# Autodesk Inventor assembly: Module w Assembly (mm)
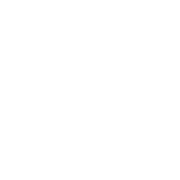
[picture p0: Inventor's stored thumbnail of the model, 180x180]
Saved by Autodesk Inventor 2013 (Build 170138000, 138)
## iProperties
Created: 2006-10
Part Number: Module w Assembly (mm)
Document SubType Name: Assembly
Designer: Wally Jones
Author: Wally Jones
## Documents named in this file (1)
- E:\!!AutoCAD Modules!!\!Inventor\Templates\Metric Templates\Modules Assembly (mm).iam
